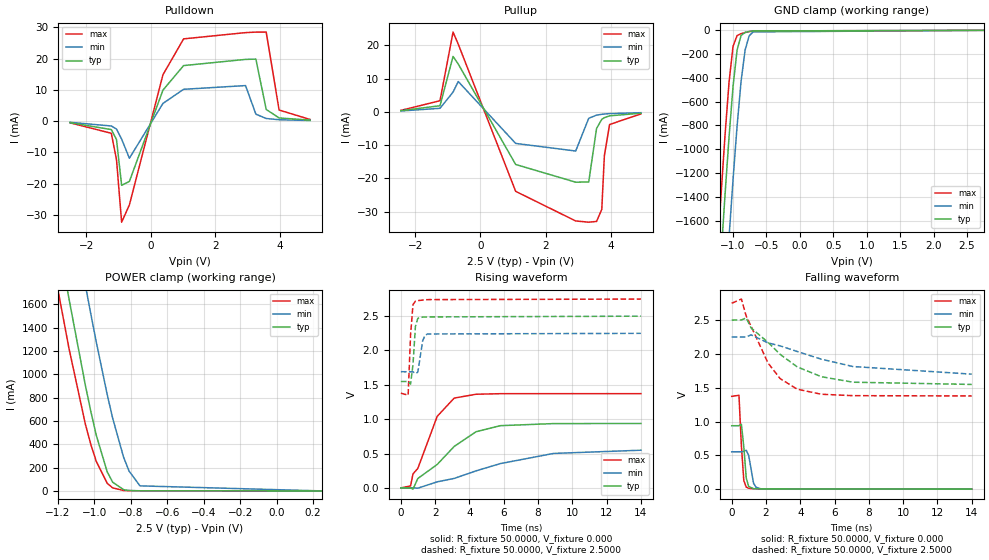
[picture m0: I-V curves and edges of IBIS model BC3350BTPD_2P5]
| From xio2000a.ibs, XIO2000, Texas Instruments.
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|   Model BC3350BTPD_2P5
[Model]   BC3350BTPD_2P5
Model_type   I/O
Polarity   Non-Inverting
Enable   Active-Low
Vinl =   0.7500V
Vinh =   1.7500V
Vmeas =   1.2500V
Cref =  15.0000pF
Rref = 100.0000M
Vref =  0.000V
C_comp   1.5797pF   1.6027pF   1.6241pF
[Model Spec]
|   typ   min   max
Vinh   1.750V   1.575V   1.925V
Vinl   0.750V   0.675V   0.825V
Vmeas   1.250V   1.125V   1.375V
[Temperature Range]   25.0000   0.1250k   -40.0000
[Voltage Range]   2.5000V   2.2500V   2.7500V
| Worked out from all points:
|   slope of the pulldown table from 0 to 0.375 V, typ, clamps not added: 38 ohm
|   slope of the pullup table from 0 to 0.375 V, typ, clamps not added: 54.3 ohm
|   GND clamp passes 1 mA (typ) near -0.59 V on its own axis
|   POWER clamp passes 1 mA (typ) near -0.75 V on its own axis
|   rising waveform, R_fixture 50.0000, V_fixture 0.000: 20-80 % time 2.32ns typ, 4.4ns min, 1.28ns max; typ from 0 V to 0.938 V
|   rising waveform, R_fixture 50.0000, V_fixture 2.5000: 20-80 % time 159ps typ, 199ps min, 172ps max; typ from 1.55 V to 2.5 V
|   falling waveform, R_fixture 50.0000, V_fixture 0.000: 20-80 % time 188ps typ, 231ps min, 187ps max; typ from 0.938 V to 0 V
|   falling waveform, R_fixture 50.0000, V_fixture 2.5000: 20-80 % time 2.84ns typ, 4.62ns min, 1.75ns max; typ from 2.5 V to 1.55 V
[Pulldown]
| voltage   I(typ)   I(min)   I(max)
-2.5V     -459uA     -348uA     -515uA
-1.22V    -2.677mA   -1.519mA   -3.847mA
-1.06V    -5.844mA   -2.506mA   -12.3mA
-900mV    -20.51mA   -5.737mA   -32.31mA
-660mV    -19.25mA   -11.84mA   -26.77mA
380mV     9.961mA    5.703mA    14.88mA
1.02V     17.81mA    10.22mA    26.36mA
2.94V     19.79mA    11.41mA    28.36mA
3.26V     19.88mA    2.268mA    28.52mA
3.58V     3.771mA    876.2uA    28.53mA
3.98V     1.046mA    481.3uA    3.587mA
4.94V     365uA      228uA      561uA
[Pullup]
| voltage   I(typ)   I(min)   I(max)
-2.44V    372uA      280uA      460uA
-1.24V    1.86mA     1.082mA    3.367mA
-840mV    16.68mA    5.954mA    24.02mA
-680mV    14.39mA    9.14mA     20.37mA
1.08V     -15.82mA   -9.485mA   -23.91mA
2.92V     -21.15mA   -11.77mA   -32.82mA
3.32V     -21.09mA   -1.924mA   -33.19mA
3.56V     -4.98mA    -966.7uA   -32.96mA
3.72V     -2.251mA   -717.3uA   -29.34mA
3.8V      -1.74mA    -634.4uA   -13.11mA
3.96V     -1.186mA   -514.3uA   -3.788mA
4.92V     -398uA     -238uA     -615uA
[GND_clamp]
| voltage   I(typ)   I(min)   I(max)
-2.5V     -14.57A    -15.39A    -14.11A
-1.24V    -2.434A    -3.317A    -1.918A
-1.18V    -1.899A    -2.778A    -1.385A
-1.12V    -1.382A    -2.25A     -881mA
-1.06V    -896.4mA   -1.74A     -435.4mA
-1V       -470.1mA   -1.253A    -133.5mA
-940mV    -166.1mA   -806.6mA   -44.23mA
-880mV    -43.23mA   -428.6mA   -27.9mA
-820mV    -17.49mA   -166.7mA   -18.56mA
-760mV    -9.789mA   -47.14mA   -10.93mA
-700mV    -5.179mA   -13.1mA    -5.218mA
2.75V     0A         0A         0A
[POWER_clamp]
| voltage   I(typ)   I(min)   I(max)
-2.49V    14.58A     15.42A     14.11A
-1.2V     2.177A     3.077A     1.722A
-1.14V    1.65A      2.542A     1.224A
-1.05V    907.7mA    1.767A     573.8mA
-1.02V    683.1mA    1.519A     399.5mA
-990mV    477.9mA    1.278A     253.5mA
-930mV    164mA      827.7mA    65.56mA
-900mV    74.97mA    624.5mA    26.15mA
-840mV    10.76mA    289.2mA    3.692mA
-810mV    4.115mA    170.7mA    1.895mA
-750mV    1.035mA    43.44mA    990.9uA
250mV     0A         0A         0A
[Ramp]
| variable   typ   min   max
dV/dt_r   0.5625/2.2941n   0.3290/4.4907n   0.8232/1.2718n
dV/dt_f   0.5705/2.8139n   0.3294/4.7136n   0.8221/1.7310n
R_load = 50.0000
[Rising Waveform]
R_fixture = 50.0000
V_fixture = 0.000
V_fixture_min = 0.000
V_fixture_max = 0.000
| time   V(typ)   V(min)   V(max)
0s        1.092nV    27.63nV    575.1pV
565.7ps   400.3uV    -183.7uV   29.17mV
707.1ps   -18.27mV   681.9uV    203.8mV
989.9ps   137mV      -3.827mV   284.1mV
2.121ns   341.5mV    88.39mV    1.042V
3.111ns   603.7mV    137.9mV    1.307V
4.384ns   817.6mV    248.1mV    1.363V
5.798ns   905.6mV    353.6mV    1.371V
8.909ns   936.1mV    501.8mV    1.372V
14ns      937.6mV    548.4mV    1.372V
[Rising Waveform]
R_fixture = 50.0000
V_fixture = 2.5000
V_fixture_min = 2.2500
V_fixture_max = 2.7500
| time   V(typ)   V(min)   V(max)
0s        1.548V     1.691V     1.378V
424.2ps   1.549V     1.69V      1.349V
565.7ps   1.511V     1.69V      2.225V
707.1ps   1.794V     1.69V      2.668V
848.5ps   2.349V     1.664V     2.717V
989.9ps   2.468V     1.685V     2.725V
1.273ns   2.486V     2.142V     2.733V
1.414ns   2.487V     2.221V     2.737V
1.556ns   2.488V     2.24V      2.74V
14ns      2.499V     2.249V     2.748V
[Falling Waveform]
R_fixture = 50.0000
V_fixture = 0.000
V_fixture_min = 0.000
V_fixture_max = 0.000
| time   V(typ)   V(min)   V(max)
0s        937.6mV    552.3mV    1.372V
424.2ps   938.1mV    553.3mV    1.388V
565.7ps   959.4mV    552.2mV    640.5mV
707.1ps   622.9mV    558.5mV    126.6mV
848.5ps   163.8mV    574.7mV    30.03mV
989.9ps   39.65mV    499.6mV    13.53mV
1.273ns   7.152mV    89.86mV    6.479mV
1.414ns   5.946mV    28.74mV    4.938mV
1.697ns   4.197mV    5.705mV    2.744mV
14ns      1.083uV    19.75uV    294nV
[Falling Waveform]
R_fixture = 50.0000
V_fixture = 2.5000
V_fixture_min = 2.2500
V_fixture_max = 2.7500
| time   V(typ)   V(min)   V(max)
0s        2.499V     2.249V     2.748V
565.7ps   2.501V     2.249V     2.81V
848.5ps   2.532V     2.249V     2.556V
1.131ns   2.382V     2.281V     2.409V
2.121ns   2.17V      2.162V     1.863V
2.828ns   1.992V     2.118V     1.634V
3.818ns   1.808V     2.035V     1.478V
5.232ns   1.662V     1.921V     1.403V
7.071ns   1.581V     1.813V     1.382V
14ns      1.548V     1.7V       1.378V
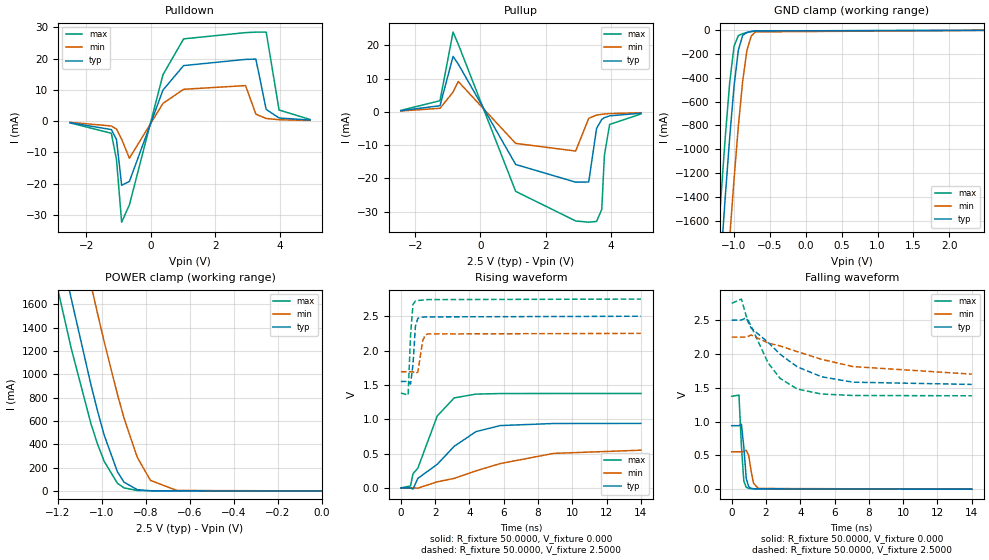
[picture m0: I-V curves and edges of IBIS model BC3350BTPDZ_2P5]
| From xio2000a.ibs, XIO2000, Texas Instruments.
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|   Model BC3350BTPDZ_2P5
[Model]   BC3350BTPDZ_2P5
Model_type   I/O
Polarity   Non-Inverting
Enable   Active-Low
Vinl =   0.7500V
Vinh =   1.7500V
Vmeas =   1.2500V
Cref =  15.0000pF
Rref = 100.0000M
Vref =  0.000V
C_comp   1.5797pF   1.6027pF   1.6241pF
[Model Spec]
|   typ   min   max
Vinh   1.750V   1.575V   1.925V
Vinl   0.750V   0.675V   0.825V
Vmeas   1.250V   1.125V   1.375V
[Temperature Range]   25.0000   0.1250k   -40.0000
[Voltage Range]   2.5000V   2.2500V   2.7500V
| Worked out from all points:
|   slope of the pulldown table from 0 to 0.375 V, typ, clamps not added: 38 ohm
|   slope of the pullup table from 0 to 0.375 V, typ, clamps not added: 54.3 ohm
|   GND clamp passes 1 mA (typ) near -0.59 V on its own axis
|   POWER clamp passes 1 mA (typ) near -0.75 V on its own axis
|   rising waveform, R_fixture 50.0000, V_fixture 0.000: 20-80 % time 2.32ns typ, 4.39ns min, 1.28ns max; typ from 0 V to 0.939 V
|   rising waveform, R_fixture 50.0000, V_fixture 2.5000: 20-80 % time 159ps typ, 199ps min, 171ps max; typ from 1.55 V to 2.5 V
|   falling waveform, R_fixture 50.0000, V_fixture 0.000: 20-80 % time 186ps typ, 229ps min, 186ps max; typ from 0.939 V to 0 V
|   falling waveform, R_fixture 50.0000, V_fixture 2.5000: 20-80 % time 2.84ns typ, 4.62ns min, 1.75ns max; typ from 2.5 V to 1.55 V
[Pulldown]
| voltage   I(typ)   I(min)   I(max)
-2.5V     -459uA     -348uA     -515uA
-1.22V    -2.677mA   -1.519mA   -3.847mA
-1.06V    -5.844mA   -2.506mA   -12.3mA
-900mV    -20.5mA    -5.737mA   -32.31mA
-660mV    -19.25mA   -11.84mA   -26.77mA
380mV     9.961mA    5.703mA    14.88mA
1.02V     17.81mA    10.22mA    26.36mA
2.94V     19.79mA    11.41mA    28.36mA
3.26V     19.88mA    2.268mA    28.52mA
3.58V     3.771mA    876.2uA    28.53mA
3.98V     1.046mA    481.2uA    3.587mA
4.94V     365uA      228uA      561uA
[Pullup]
| voltage   I(typ)   I(min)   I(max)
-2.44V    372uA      280uA      461uA
-1.24V    1.86mA     1.082mA    3.367mA
-840mV    16.68mA    5.954mA    24.02mA
-680mV    14.39mA    9.14mA     20.37mA
1.08V     -15.82mA   -9.485mA   -23.91mA
2.92V     -21.15mA   -11.77mA   -32.82mA
3.32V     -21.09mA   -1.924mA   -33.19mA
3.56V     -4.98mA    -966.6uA   -32.96mA
3.72V     -2.251mA   -717.3uA   -29.34mA
3.8V      -1.74mA    -634.3uA   -13.11mA
3.96V     -1.186mA   -514.3uA   -3.788mA
4.92V     -398uA     -238uA     -614uA
[GND_clamp]
| voltage   I(typ)   I(min)   I(max)
-2.5V     -14.57A    -15.39A    -14.11A
-1.24V    -2.434A    -3.317A    -1.918A
-1.18V    -1.899A    -2.778A    -1.385A
-1.12V    -1.382A    -2.25A     -881mA
-1.06V    -896.4mA   -1.74A     -435.3mA
-1V       -470.1mA   -1.253A    -133.5mA
-940mV    -166.1mA   -806.6mA   -44.14mA
-880mV    -43.19mA   -428.6mA   -27.79mA
-820mV    -17.44mA   -166.7mA   -18.46mA
-760mV    -9.734mA   -47.13mA   -10.84mA
-700mV    -5.127mA   -13.09mA   -5.132mA
2.48V     111.8pA    195nA      93.15pA
[POWER_clamp]
| voltage   I(typ)   I(min)   I(max)
-2.49V    14.58A     15.42A     14.11A
-1.2V     2.177A     3.077A     1.722A
-1.14V    1.65A      2.542A     1.223A
-1.05V    907.7mA    1.767A     573.8mA
-1.02V    683mA      1.519A     399.4mA
-990mV    477.9mA    1.278A     253.4mA
-930mV    163.9mA    827.7mA    65.48mA
-900mV    74.93mA    624.5mA    26.06mA
-840mV    10.71mA    289.2mA    3.596mA
-780mV    1.796mA    90.25mA    1.191mA
-660mV    334uA      3.822mA    368.9uA
0V        114.6pA    2.17nA     109.7pA
[Ramp]
| variable   typ   min   max
dV/dt_r   0.5636/2.2927n   0.3295/4.4889n   0.8251/1.2722n
dV/dt_f   0.5698/2.8110n   0.3291/4.7098n   0.8206/1.7291n
R_load = 50.0000
[Rising Waveform]
R_fixture = 50.0000
V_fixture = 0.000
V_fixture_min = 0.000
V_fixture_max = 0.000
| time   V(typ)   V(min)   V(max)
0s        1.093nV    27.66nV    576pV
565.7ps   408.4uV    -184.6uV   29.2mV
707.1ps   -18.38mV   683.7uV    206.9mV
989.9ps   138.7mV    -3.842mV   286.4mV
2.121ns   343.3mV    88.64mV    1.047V
3.111ns   606mV      138.4mV    1.311V
4.384ns   819.8mV    248.7mV    1.366V
5.798ns   907.6mV    354.4mV    1.374V
8.909ns   937.9mV    502.6mV    1.375V
14ns      939.4mV    549.1mV    1.375V
[Rising Waveform]
R_fixture = 50.0000
V_fixture = 2.5000
V_fixture_min = 2.2500
V_fixture_max = 2.7500
| time   V(typ)   V(min)   V(max)
0s        1.55V      1.692V     1.382V
424.2ps   1.551V     1.691V     1.353V
565.7ps   1.514V     1.692V     2.231V
707.1ps   1.797V     1.692V     2.672V
848.5ps   2.351V     1.666V     2.721V
989.9ps   2.47V      1.687V     2.728V
1.273ns   2.488V     2.143V     2.736V
1.414ns   2.489V     2.222V     2.74V
1.556ns   2.49V      2.242V     2.742V
14ns      2.5V       2.25V      2.75V
[Falling Waveform]
R_fixture = 50.0000
V_fixture = 0.000
V_fixture_min = 0.000
V_fixture_max = 0.000
| time   V(typ)   V(min)   V(max)
0s        939.4mV    553.1mV    1.375V
424.2ps   939.9mV    554mV      1.391V
565.7ps   961.4mV    552.9mV    638.3mV
707.1ps   622.8mV    559.3mV    120mV
848.5ps   158.8mV    575.6mV    26.76mV
989.9ps   35.93mV    500.1mV    12.03mV
1.131ns   10.8mV     270.6mV    7.945mV
1.273ns   6.201mV    87.45mV    5.873mV
1.556ns   4.498mV    10.04mV    3.41mV
14ns      1.082uV    19.67uV    292.4nV
[Falling Waveform]
R_fixture = 50.0000
V_fixture = 2.5000
V_fixture_min = 2.2500
V_fixture_max = 2.7500
| time   V(typ)   V(min)   V(max)
0s        2.5V       2.25V      2.75V
565.7ps   2.503V     2.25V      2.813V
848.5ps   2.535V     2.25V      2.56V
1.131ns   2.384V     2.281V     2.413V
2.121ns   2.173V     2.163V     1.868V
2.828ns   1.995V     2.119V     1.638V
3.818ns   1.811V     2.036V     1.482V
5.232ns   1.664V     1.922V     1.408V
7.071ns   1.583V     1.814V     1.386V
14ns      1.55V      1.702V     1.382V
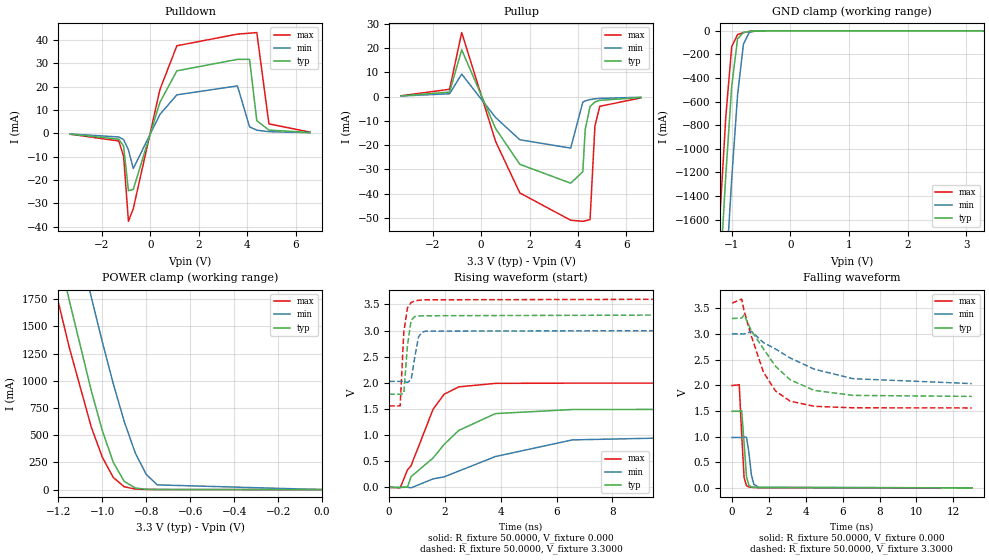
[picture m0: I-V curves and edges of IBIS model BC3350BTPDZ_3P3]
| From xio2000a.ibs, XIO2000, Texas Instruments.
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|   Model BC3350BTPDZ_3P3
[Model]   BC3350BTPDZ_3P3
Model_type   I/O
Polarity   Non-Inverting
Enable   Active-Low
Vinl =   0.9900V
Vinh =   2.3100V
Vmeas =   1.6500V
Cref =  15.0000pF
Rref = 100.0000M
Vref =  0.000V
C_comp   1.9708pF   2.0638pF   1.9731pF
[Model Spec]
|   typ   min   max
Vinh   2.31V   2.10V   2.52V
Vinl   0.99V   0.90V   1.08V
Vmeas   1.65V   1.50V   1.80V
[Temperature Range]   25.0000   0.1250k   -40.0000
[Voltage Range]   3.3000V   3.0000V   3.6000V
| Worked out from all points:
|   slope of the pulldown table from 0 to 0.495 V, typ, clamps not added: 31.4 ohm
|   slope of the pullup table from 0 to 0.495 V, typ, clamps not added: 44.5 ohm
|   GND clamp passes 1 mA (typ) near -0.59 V on its own axis
|   POWER clamp passes 1 mA (typ) near -0.75 V on its own axis
|   rising waveform, R_fixture 50.0000, V_fixture 0.000: 20-80 % time 1.63ns typ, 3.18ns min, 928ps max; typ from 0 V to 1.49 V
|   rising waveform, R_fixture 50.0000, V_fixture 3.3000: 20-80 % time 167ps typ, 189ps min, 156ps max; typ from 1.78 V to 3.3 V
|   falling waveform, R_fixture 50.0000, V_fixture 0.000: 20-80 % time 181ps typ, 217ps min, 176ps max; typ from 1.49 V to 0 V
|   falling waveform, R_fixture 50.0000, V_fixture 3.3000: 20-80 % time 2.06ns typ, 3.39ns min, 1.33ns max; typ from 3.3 V to 1.78 V
[Pulldown]
| voltage   I(typ)   I(min)   I(max)
-3.3V     -363uA     -289uA     -392uA
-1.3V     -2.499mA   -1.558mA   -3.272mA
-1.1V     -5.495mA   -2.673mA   -9.753mA
-900mV    -24.57mA   -7.086mA   -37.63mA
-700mV    -23.98mA   -15.08mA   -32.22mA
400mV     13.29mA    8.099mA    18.71mA
1.1V      26.74mA    16.46mA    37.45mA
3.6V      31.62mA    20.28mA    42.43mA
4.1V      31.65mA    2.775mA    42.82mA
4.4V      5.418mA    1.337mA    43.09mA
4.9V      1.364mA    700.9uA    4.045mA
6.6V      367uA      263uA      482uA
[Pullup]
| voltage   I(typ)   I(min)   I(max)
-3.3V     276uA      222uA      319uA
-1.3V     1.831mA    1.157mA    3.006mA
-800mV    19.29mA    9.256mA    26.38mA
600mV     -13.2mA    -8.655mA   -18.5mA
1.6V      -27.94mA   -17.82mA   -39.75mA
3.7V      -35.73mA   -21.26mA   -51mA
4.2V      -31.01mA   -2.304mA   -51.44mA
4.3V      -13.58mA   -1.804mA   -51.23mA
4.5V      -4.094mA   -1.249mA   -50.72mA
4.7V      -2.272mA   -950.1uA   -12.21mA
4.9V      -1.556mA   -765.1uA   -4.03mA
6.6V      -413uA     -285uA     -545uA
[GND_clamp]
| voltage   I(typ)   I(min)   I(max)
-3.3V     -22.46A    -23.25A    -22.02A
-1.3V     -2.981A    -3.864A    -2.466A
-1.2V     -2.075A    -2.956A    -1.561A
-1.1V     -1.216A    -2.078A    -723.3mA
-1V       -470.1mA   -1.253A    -133.5mA
-900mV    -66.71mA   -544.3mA   -31.64mA
-800mV    -14.21mA   -112.3mA   -15.74mA
-700mV    -5.127mA   -13.09mA   -5.132mA
-600mV    -1.059mA   -2.3mA     -715.9uA
-400mV    -6.019uA   -45.28uA   -1.112uA
3.3V      155.2pA    1.105uA    124.9pA
[POWER_clamp]
| voltage   I(typ)   I(min)   I(max)
-3.3V     22.56A     23.38A     22.11A
-1.25V    2.627A     3.53A      2.158A
-1.2V     2.177A     3.077A     1.722A
-1.15V    1.736A     2.631A     1.304A
-1.05V    907.7mA    1.767A     573.8mA
-1V       543.6mA    1.358A     298.7mA
-950mV    250.4mA    972.4mA    111.1mA
-900mV    74.93mA    624.5mA    26.06mA
-850mV    15.02mA    336.8mA    4.862mA
-800mV    3.029mA    139.7mA    1.53mA
-750mV    983.5uA    43.42mA    893.5uA
0V        155.2pA    2.74nA     144.1pA
[Ramp]
| variable   typ   min   max
dV/dt_r   0.8954/1.6133n   0.5882/3.1510n   1.1967/0.9192n
dV/dt_f   0.9109/2.0429n   0.5806/3.3595n   1.2256/1.3213n
R_load = 50.0000
[Rising Waveform]
R_fixture = 50.0000
V_fixture = 0.000
V_fixture_min = 0.000
V_fixture_max = 0.000
| time   V(typ)   V(min)   V(max)
0s        1.535nV    33.99nV    724.7pV
393.9ps   892.9uV    -12.59uV   -9.215mV
656.6ps   6.864mV    1.945mV    333.6mV
787.9ps   205.4mV    -8.264mV   417.5mV
1.576ns   562.5mV    162.9mV    1.495V
1.97ns    820.4mV    200.7mV    1.781V
2.495ns   1.089V     311.8mV    1.922V
3.808ns   1.411V     589.5mV    1.989V
6.566ns   1.489V     908mV      1.994V
13ns      1.492V     980.3mV    1.994V
[Rising Waveform]
R_fixture = 50.0000
V_fixture = 3.3000
V_fixture_min = 3.0000
V_fixture_max = 3.6000
| time   V(typ)   V(min)   V(max)
0s        1.782V     2.028V     1.557V
393.9ps   1.782V     2.027V     1.558V
525.3ps   1.796V     2.029V     2.971V
656.6ps   2.718V     2.006V     3.434V
787.9ps   3.195V     2.059V     3.535V
919.2ps   3.267V     2.492V     3.567V
1.051ns   3.277V     2.877V     3.578V
1.182ns   3.28V      2.969V     3.583V
1.313ns   3.282V     2.988V     3.587V
13ns      3.3V       3V         3.6V
[Falling Waveform]
R_fixture = 50.0000
V_fixture = 0.000
V_fixture_min = 0.000
V_fixture_max = 0.000
| time   V(typ)   V(min)   V(max)
0s        1.492V     981.6mV    1.994V
393.9ps   1.493V     982.5mV    2.009V
525.3ps   1.504V     981.5mV    1.04V
656.6ps   872.4mV    993.1mV    201.7mV
787.9ps   215mV      984.3mV    42.64mV
919.2ps   48.51mV    684.9mV    15.65mV
1.051ns   16.52mV    255.2mV    10.73mV
1.182ns   10.39mV    70.59mV    7.904mV
1.444ns   6.791mV    9.904mV    4.275mV
13ns      677.3nV    10.11uV    291.6nV
[Falling Waveform]
R_fixture = 50.0000
V_fixture = 3.3000
V_fixture_min = 3.0000
V_fixture_max = 3.6000
| time   V(typ)   V(min)   V(max)
0s        3.3V       3V         3.6V
525.3ps   3.31V      3V         3.678V
656.6ps   3.369V     2.997V     3.449V
1.051ns   3.063V     3.05V      2.956V
1.707ns   2.71V      2.831V     2.253V
2.364ns   2.368V     2.707V     1.886V
3.152ns   2.107V     2.531V     1.69V
4.465ns   1.899V     2.312V     1.589V
6.566ns   1.802V     2.127V     1.56V
13ns      1.782V     2.032V     1.557V
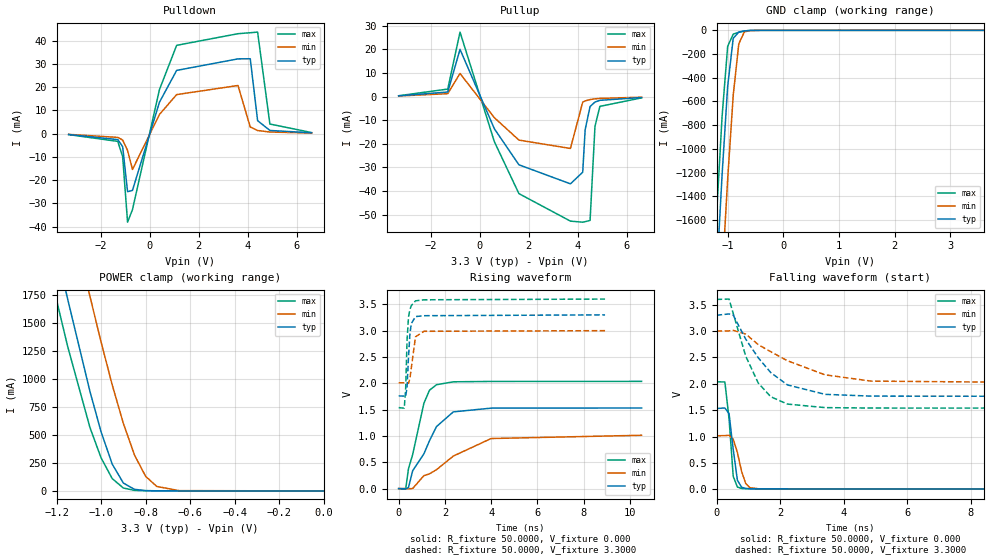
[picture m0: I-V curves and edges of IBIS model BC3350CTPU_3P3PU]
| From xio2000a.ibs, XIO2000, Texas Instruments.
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|   Model BC3350CTPU_3P3PU
[Model]   BC3350CTPU_3P3PU
Model_type   I/O
Polarity   Non-Inverting
Enable   Active-Low
Vinl =   0.9900V
Vinh =   2.3100V
Vmeas =   1.6500V
Cref =  15.0000pF
Rref = 100.0000M
Vref =  0.000V
C_comp   1.9215pF   2.0161pF   1.9194pF
[Temperature Range]   25.0000   0.1250k   -40.0000
[Voltage Range]   3.3000V   3.0000V   3.6000V
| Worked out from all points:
|   slope of the pulldown table from 0 to 0.495 V, typ, clamps not added: 30.8 ohm
|   slope of the pullup table from 0 to 0.495 V, typ, clamps not added: 43 ohm
|   GND clamp passes 1 mA (typ) near -0.58 V on its own axis
|   POWER clamp passes 1 mA (typ) near -0.74 V on its own axis
|   rising waveform, R_fixture 50.0000, V_fixture 0.000: 20-80 % time 1.13ns typ, 2.16ns min, 657ps max; typ from 0.002 V to 1.53 V
|   rising waveform, R_fixture 50.0000, V_fixture 3.3000: 20-80 % time 125ps typ, 163ps min, 108ps max; typ from 1.76 V to 3.3 V
|   falling waveform, R_fixture 50.0000, V_fixture 0.000: 20-80 % time 192ps typ, 268ps min, 166ps max; typ from 1.53 V to 0.002 V
|   falling waveform, R_fixture 50.0000, V_fixture 3.3000: 20-80 % time 1.21ns typ, 2.01ns min, 802ps max; typ from 3.3 V to 1.76 V
[Pulldown]
| voltage   I(typ)   I(min)   I(max)
-3.3V     -368uA     -295uA     -396uA
-1.3V     -2.536mA   -1.588mA   -3.308mA
-1.1V     -5.574mA   -2.722mA   -9.853mA
-900mV    -24.94mA   -7.21mA    -38.07mA
-700mV    -24.39mA   -15.39mA   -32.64mA
400mV     13.55mA    8.28mA     19mA
1.1V      27.23mA    16.82mA    38.01mA
3.6V      32.19mA    20.74mA    43.02mA
4.1V      32.24mA    2.869mA    43.43mA
4.4V      5.593mA    1.375mA    43.71mA
4.9V      1.396mA    719.1uA    4.161mA
6.6V      374uA      270uA      490uA
[Pullup]
| voltage   I(typ)   I(min)   I(max)
-3.3V     287uA      231uA      331uA
-1.3V     1.913mA    1.209mA    3.156mA
-800mV    19.97mA    9.765mA    27.29mA
600mV     -13.66mA   -8.958mA   -19.14mA
1.6V      -28.91mA   -18.45mA   -41.12mA
3.7V      -36.98mA   -22mA      -52.77mA
4.2V      -32.06mA   -2.382mA   -53.22mA
4.3V      -14.02mA   -1.866mA   -53mA
4.5V      -4.234mA   -1.292mA   -52.47mA
4.7V      -2.35mA    -983uA     -12.63mA
4.9V      -1.61mA    -791.8uA   -4.169mA
6.6V      -427uA     -295uA     -564uA
[GND_clamp]
| voltage   I(typ)   I(min)   I(max)
-3.3V     -22.46A    -23.25A    -22.02A
-1.3V     -2.984A    -3.868A    -2.468A
-1.2V     -2.078A    -2.96A     -1.563A
-1.1V     -1.218A    -2.081A    -725.3mA
-1V       -472.1mA   -1.256A    -134.6mA
-900mV    -67.44mA   -546.8mA   -32.21mA
-800mV    -14.49mA   -113.3mA   -16.11mA
-700mV    -5.296mA   -13.28mA   -5.367mA
-600mV    -1.174mA   -2.386mA   -889.7uA
-400mV    -107.2uA   -106uA     -164.8uA
3.6V      0A         0A         0A
[POWER_clamp]
| voltage   I(typ)   I(min)   I(max)
-3.3V     22.54A     23.35A     22.1A
-1.2V     2.157A     3.049A     1.709A
-1.15V    1.717A     2.603A     1.293A
-1.05V    891mA      1.742A     568.1mA
-1V       529.4mA    1.333A     296.2mA
-950mV    240.5mA    949.8mA    110.5mA
-900mV    70.83mA    604.8mA    26.11mA
-850mV    14.22mA    321.8mA    5.008mA
-800mV    2.986mA    131.1mA    1.668mA
-750mV    1.048mA    40.21mA    1.014mA
-650mV    361.8uA    2.754mA    415.4uA
0V        145pA      2.769nA    132.7pA
[Ramp]
| variable   typ   min   max
dV/dt_r   0.9181/1.1046n   0.6075/2.1596n   1.2207/0.6398n
dV/dt_f   0.9236/1.1963n   0.5942/1.9892n   1.2365/0.7942n
R_load = 50.0000
[Rising Waveform]
R_fixture = 50.0000
V_fixture = 0.000
V_fixture_min = 0.000
V_fixture_max = 0.000
| time   V(typ)   V(min)   V(max)
0s        1.67mV     1.354mV    2.118mV
303ps     -2.132mV   2.789mV    -9.431mV
424.2ps   21.33mV    -2.054mV   379.1mV
606.1ps   341.8mV    2.808mV    649.1mV
1.091ns   660.8mV    247.5mV    1.621V
1.333ns   910.6mV    281.5mV    1.869V
1.636ns   1.179V     360.4mV    1.974V
2.364ns   1.458V     619.1mV    2.029V
4ns       1.529V     952.1mV    2.036V
10.51ns   1.532V     1.014V     2.037V
[Rising Waveform]
R_fixture = 50.0000
V_fixture = 3.3000
V_fixture_min = 3.0000
V_fixture_max = 3.6000
| time   V(typ)   V(min)   V(max)
0s        1.761V     2.01V      1.539V
242.4ps   1.757V     2.011V     1.528V
303ps     1.748V     2.008V     1.903V
363.6ps   1.937V     1.995V     2.824V
424.2ps   2.489V     2.001V     3.256V
484.8ps   2.933V     2.084V     3.401V
545.5ps   3.135V     2.288V     3.474V
727.3ps   3.267V     2.883V     3.566V
1.091ns   3.284V     2.988V     3.586V
8.929ns   3.3V       3V         3.6V
[Falling Waveform]
R_fixture = 50.0000
V_fixture = 0.000
V_fixture_min = 0.000
V_fixture_max = 0.000
| time   V(typ)   V(min)   V(max)
0s        1.532V     1.014V     2.037V
262.6ps   1.541V     1.017V     2.035V
393.9ps   1.435V     1.023V     1.339V
525.3ps   753.3mV    946.7mV    244.8mV
656.6ps   170.8mV    697.9mV    41.65mV
787.9ps   37.54mV    339.3mV    14.43mV
919.2ps   15.12mV    107mV      10.58mV
1.051ns   10.2mV     29.18mV    8.496mV
1.313ns   7.196mV    8.953mV    5.843mV
13ns      1.671mV    1.355mV    2.118mV
[Falling Waveform]
R_fixture = 50.0000
V_fixture = 3.3000
V_fixture_min = 3.0000
V_fixture_max = 3.6000
| time   V(typ)   V(min)   V(max)
0s        3.3V       3V         3.6V
393.9ps   3.325V     3.003V     3.607V
525.3ps   3.303V     3.013V     3.333V
919.2ps   2.846V     2.943V     2.523V
1.313ns   2.493V     2.743V     2.014V
1.707ns   2.212V     2.608V     1.754V
2.232ns   1.978V     2.437V     1.615V
3.414ns   1.8V       2.17V      1.548V
4.859ns   1.766V     2.051V     1.54V
13ns      1.761V     2.01V      1.539V
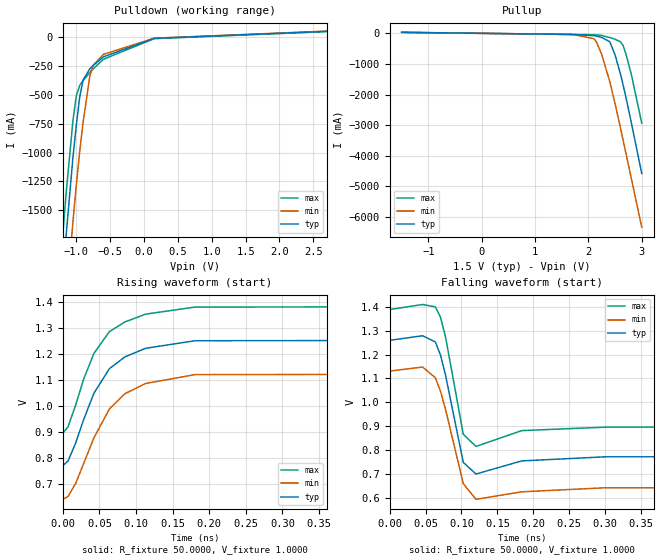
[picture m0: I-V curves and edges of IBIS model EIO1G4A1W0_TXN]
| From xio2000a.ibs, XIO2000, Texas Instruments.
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|   Model EIO1G4A1W0_TXN
[Model]   EIO1G4A1W0_TXN
Model_type   Output
Polarity   Inverting
Vmeas =   1.0000V
Cref =   5.0000pF
Rref =  50.0000
Vref =   1.0000V
C_comp   1.6030pF   1.6370pF   1.5940pF
[Temperature Range]   25.0000   0.1250k   -40.0000
[Voltage Range]   1.5000V   1.3500V   1.6500V
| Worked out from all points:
|   slope of the pulldown table from 0 to 0.225 V, typ, clamps not added: 10 ohm
|   slope of the pullup table from 0 to 0.225 V, typ, clamps not added: 46 ohm
|   rising waveform, R_fixture 50.0000, V_fixture 1.0000: 20-80 % time 51.5ps typ, 55.3ps min, 49.4ps max; typ from 0.771 V to 1.26 V
|   falling waveform, R_fixture 50.0000, V_fixture 1.0000: 20-80 % time 20.7ps typ, 23.5ps min, 18.6ps max; typ from 1.26 V to 0.771 V
[Pulldown]
| voltage   I(typ)   I(min)   I(max)
-1.5V     -4.594A    -5.121A    -4.265A
-1.2V     -2.088A    -2.699A    -1.715A
-1.15V    -1.711A    -2.315A    -1.349A
-1.05V    -1.044A    -1.599A    -725.2mA
-1V       -764.5mA   -1.279A    -509.2mA
-950mV    -519.8mA   -991.5mA   -420.4mA
-900mV    -374.6mA   -737.8mA   -377.8mA
-800mV    -276.3mA   -337.6mA   -309.1mA
-750mV    -247.3mA   -245.7mA   -276.8mA
-600mV    -173.7mA   -152.2mA   -194.5mA
150mV     -13.82mA   -12.24mA   -16.25mA
3V        53.89mA    56.06mA    51.37mA
[Pullup]
| voltage   I(typ)   I(min)   I(max)
-1.5V     32.86mA    32.06mA    33.4mA
1.7V      -36.49mA   -36.27mA   -37.34mA
2.1V      -73.38mA   -171.4mA   -47.12mA
2.15V     -90.76mA   -274.2mA   -50.59mA
2.25V     -134.3mA   -692.4mA   -69.55mA
2.4V      -273mA     -1.573A    -136.4mA
2.5V      -704.7mA   -2.297A    -194.4mA
2.6V      -1.321A    -3.082A    -274.5mA
2.65V     -1.68A     -3.486A    -397mA
2.7V      -2.064A    -3.891A    -652.6mA
2.8V      -2.879A    -4.703A    -1.302A
3V        -4.58A     -6.332A    -2.931A
[Ramp]
| variable   typ   min   max
dV/dt_r   0.5584/44.3883p   0.5611/45.7199p   0.5597/43.7523p
dV/dt_f   0.5574/44.3490p   0.5591/45.0689p   0.5594/43.5451p
R_load = 50.0000
[Rising Waveform]
R_fixture = 50.0000
V_fixture = 1.0000
V_fixture_min = 0.9000
V_fixture_max = 1.1000
| time   V(typ)   V(min)   V(max)
0s        770.8mV    641.7mV    895.5mV
7.071ps   788.1mV    652.4mV    919.2mV
17.68ps   858.4mV    703.3mV    1.004V
28.28ps   945.7mV    777.7mV    1.101V
42.42ps   1.048V     877.1mV    1.201V
63.64ps   1.143V     988.3mV    1.285V
84.85ps   1.188V     1.047V     1.322V
113.1ps   1.221V     1.086V     1.352V
180.3ps   1.25V      1.12V      1.379V
3.03ns    1.26V      1.131V     1.389V
[Falling Waveform]
R_fixture = 50.0000
V_fixture = 1.0000
V_fixture_min = 0.9000
V_fixture_max = 1.1000
| time   V(typ)   V(min)   V(max)
0s        1.26V      1.131V     1.389V
45.96ps   1.279V     1.148V     1.41V
63.64ps   1.253V     1.103V     1.4V
70.71ps   1.199V     1.047V     1.357V
77.78ps   1.114V     970.5mV    1.274V
102.5ps   748.3mV    659.3mV    866.3mV
120.2ps   699.7mV    593.7mV    815.3mV
183.8ps   754.7mV    625.2mV    881.7mV
300.5ps   771.9mV    642.2mV    896.1mV
16.36ns   770.7mV    641.6mV    895.4mV
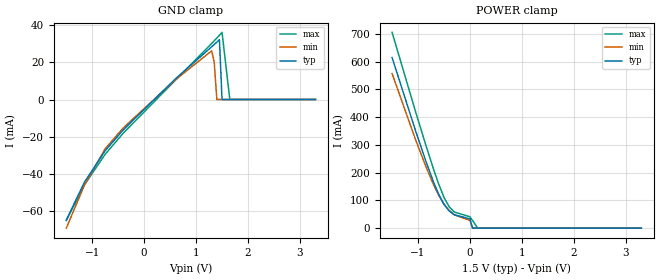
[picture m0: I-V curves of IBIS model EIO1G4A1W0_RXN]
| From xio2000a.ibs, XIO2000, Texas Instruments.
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|   Model EIO1G4A1W0_RXN
[Model]   EIO1G4A1W0_RXN
Model_type   Input
Polarity   Inverting
Vinl =  -0.6000V
Vinh =   0.6000V
C_comp   1.6030pF   1.6370pF   1.5940pF
[Model Spec]
|   typ   min   max
Vinh   0.5V   0.175V   0.6V
Vinl   -0.5V   -0.175V   -0.6V
[Temperature Range]   25.0000   0.1250k   -40.0000
[Voltage Range]   1.5000V   1.3500V   1.6500V
[GND_clamp]
| voltage   I(typ)   I(min)   I(max)
-1.5V     -64.97mA   -69.31mA   -65.2mA
-1.15V    -44.52mA   -46.11mA   -45.96mA
-750mV    -27.56mA   -26.49mA   -29.48mA
-400mV    -16.25mA   -15.22mA   -18.06mA
600mV     11.08mA    10.55mA    10.36mA
1.3V      28.4mA     26.23mA    30.18mA
1.35V     29.62mA    20mA       31.65mA
1.4V      30.89mA    0A         33.14mA
1.45V     32.23mA    0A         34.64mA
1.5V      0A         0A         36.17mA
1.65V     0A         0A         0A
3.3V      0A         0A         0A
[POWER_clamp]
| voltage   I(typ)   I(min)   I(max)
-1.5V     614.8mA    557.3mA    705.7mA
-1.05V    352.1mA    319.7mA    421.1mA
-850mV    241.7mA    222.3mA    299mA
-700mV    165.3mA    156mA      211.5mA
-600mV    120.8mA    117.7mA    157.4mA
-500mV    85.49mA    86.52mA    110.5mA
-400mV    61.9mA     63.55mA    76.75mA
-300mV    47.91mA    47.78mA    57.85mA
0V        33.62mA    27.69mA    41.02mA
50mV      0A         0A         27.35mA
150mV     0A         0A         0A
3.3V      0A         0A         0A
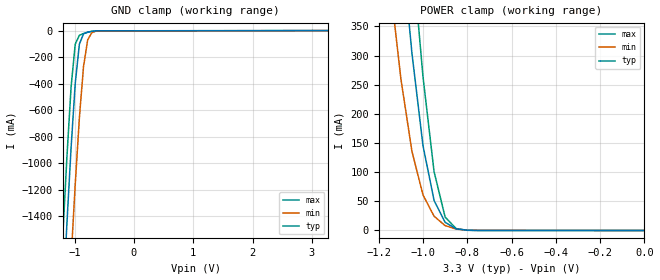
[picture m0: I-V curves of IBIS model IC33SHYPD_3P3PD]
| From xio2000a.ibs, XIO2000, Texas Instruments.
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|   Model IC33SHYPD_3P3PD
[Model]   IC33SHYPD_3P3PD
Model_type   Input
Polarity   Non-Inverting
Vinl =   0.9900V
Vinh =   2.3100V
C_comp   2.0800pF   2.0800pF   2.0800pF
[Model Spec]
|   typ   min   max
Vinh   2.31V   2.10V   2.52V
Vinl   0.99V   0.90V   1.08V
[Temperature Range]   25.0000   0.1250k   -40.0000
[Voltage Range]   3.3000V   3.0000V   3.6000V
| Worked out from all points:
|   GND clamp passes 1 mA (typ) near -0.59 V on its own axis
|   POWER clamp passes 1 mA (typ) near -0.81 V on its own axis
| (Vdd votage range)   1.50V   1.35V   1.65V
| (Process strength)   nominal   weak   strong
[GND_clamp]
| voltage   I(typ)   I(min)   I(max)
-3.3V     -22.44A    -23.23A    -22.01A
-1.2V     -2.062A    -2.938A    -1.55A
-1.13V    -1.453A    -2.319A    -952.1mA
-1.06V    -884.3mA   -1.722A    -427mA
-990mV    -399.1mA   -1.159A    -102.3mA
-920mV    -102mA     -657.3mA   -35.66mA
-850mV    -24.66mA   -270.7mA   -22.38mA
-780mV    -11.46mA   -70.03mA   -12.94mA
-710mV    -5.644mA   -15.31mA   -5.841mA
-640mV    -2.142mA   -4.307mA   -1.755mA
3.28V     193.2pA    3.222nA    168.3pA
[POWER_clamp]
| voltage   I(typ)   I(min)   I(max)
-3.3V     12.64A     11.74A     13.39A
-1.15V    732.8mA    427.8mA    979.7mA
-1.1V     506.2mA    260.6mA    722.8mA
-1.05V    304.3mA    136mA      480.1mA
-1V       145.5mA    61.04mA    263.8mA
-950mV    51.56mA    24.44mA    101mA
-900mV    14.01mA    8.383mA    22.94mA
-850mV    2.793mA    2.36mA     3.142mA
-800mV    442.5uA    587.5uA    300.2uA
-750mV    66.2uA     140.7uA    26.86uA
0V        195.4pA    2.747nA    187.9pA
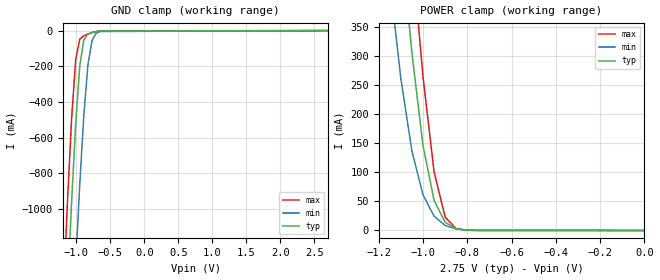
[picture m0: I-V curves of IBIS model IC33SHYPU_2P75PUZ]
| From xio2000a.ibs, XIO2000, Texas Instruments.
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|   Model IC33SHYPU_2P75PUZ
[Model]   IC33SHYPU_2P75PUZ
Model_type   Input
Polarity   Non-Inverting
Vinl =   0.8200V
Vinh =   1.9300V
C_comp   1.6800pF   1.6800pF   1.6800pF
[Temperature Range]   25.0000   0.1250k   -40.0000
[Voltage Range]   2.7500V   2.5000V   3.0000V
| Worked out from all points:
|   GND clamp passes 1 mA (typ) near -0.60 V on its own axis
|   POWER clamp passes 1 mA (typ) near -0.81 V on its own axis
[GND_clamp]
| voltage   I(typ)   I(min)   I(max)
-2.75V    -17.02A    -17.82A    -16.57A
-1.19V    -1.973A    -2.848A    -1.462A
-1.13V    -1.453A    -2.319A    -952mA
-1.07V    -961.9mA   -1.806A    -494.2mA
-1.01V    -524.4mA   -1.315A    -162.9mA
-950mV    -197.8mA   -862.4mA   -48.41mA
-890mV    -51.2mA    -472.9mA   -28.94mA
-830mV    -18.95mA   -192.8mA   -19.47mA
-770mV    -10.44mA   -56.11mA   -11.77mA
-710mV    -5.643mA   -15.28mA   -5.841mA
-650mV    -2.514mA   -5.077mA   -2.147mA
2.71V     148pA      3.084nA    129.4pA
[POWER_clamp]
| voltage   I(typ)   I(min)   I(max)
-2.75V    9.52A      8.73A      10.17A
-1.15V    732.9mA    428mA      979.8mA
-1.1V     506.3mA    260.8mA    722.9mA
-1.05V    304.4mA    136.2mA    480.2mA
-1V       145.7mA    61.22mA    263.9mA
-950mV    51.67mA    24.6mA     101mA
-900mV    14.1mA     8.529mA    22.97mA
-850mV    2.852mA    2.482mA    3.15mA
-800mV    471.9uA    685.4uA    302.8uA
-750mV    76.24uA    214.6uA    28.26uA
0V        151.6pA    2.342nA    146.6pA
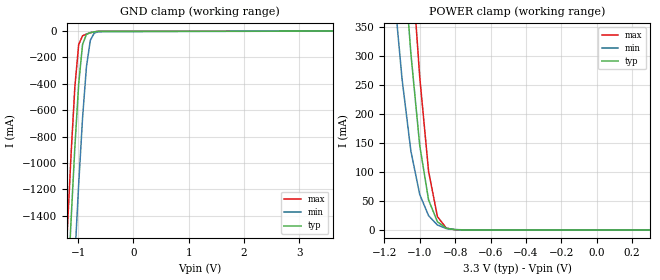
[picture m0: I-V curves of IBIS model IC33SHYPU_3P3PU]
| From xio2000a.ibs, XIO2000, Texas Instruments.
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|   Model IC33SHYPU_3P3PU
[Model]   IC33SHYPU_3P3PU
Model_type   Input
Polarity   Non-Inverting
Vinl =   0.9900V
Vinh =   2.3100V
C_comp   2.0800pF   2.0800pF   2.0800pF
[Temperature Range]   25.0000   0.1250k   -40.0000
[Voltage Range]   3.3000V   3.0000V   3.6000V
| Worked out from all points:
|   GND clamp passes 1 mA (typ) near -0.59 V on its own axis
|   POWER clamp passes 1 mA (typ) near -0.81 V on its own axis
[GND_clamp]
| voltage   I(typ)   I(min)   I(max)
-3.3V     -22.44A    -23.23A    -22.01A
-1.2V     -2.062A    -2.938A    -1.55A
-1.13V    -1.453A    -2.319A    -952.1mA
-1.06V    -884.3mA   -1.722A    -427mA
-990mV    -399.1mA   -1.159A    -102.3mA
-920mV    -102mA     -657.3mA   -35.8mA
-850mV    -24.73mA   -270.7mA   -22.54mA
-780mV    -11.56mA   -70.04mA   -13.1mA
-710mV    -5.743mA   -15.34mA   -6.004mA
-640mV    -2.243mA   -4.356mA   -1.919mA
3.6V      0A         17uA       0A
[POWER_clamp]
| voltage   I(typ)   I(min)   I(max)
-3.3V     12.64A     11.74A     13.39A
-1.15V    732.9mA    428mA      979.8mA
-1.1V     506.3mA    260.8mA    722.9mA
-1.05V    304.4mA    136.2mA    480.2mA
-1V       145.7mA    61.22mA    263.9mA
-950mV    51.68mA    24.61mA    101.1mA
-900mV    14.11mA    8.533mA    23.04mA
-850mV    2.879mA    2.487mA    3.244mA
-800mV    512.7uA    692.1uA    396.8uA
-750mV    128.4uA    223.3uA    117.1uA
300mV     0A         1nA        0A
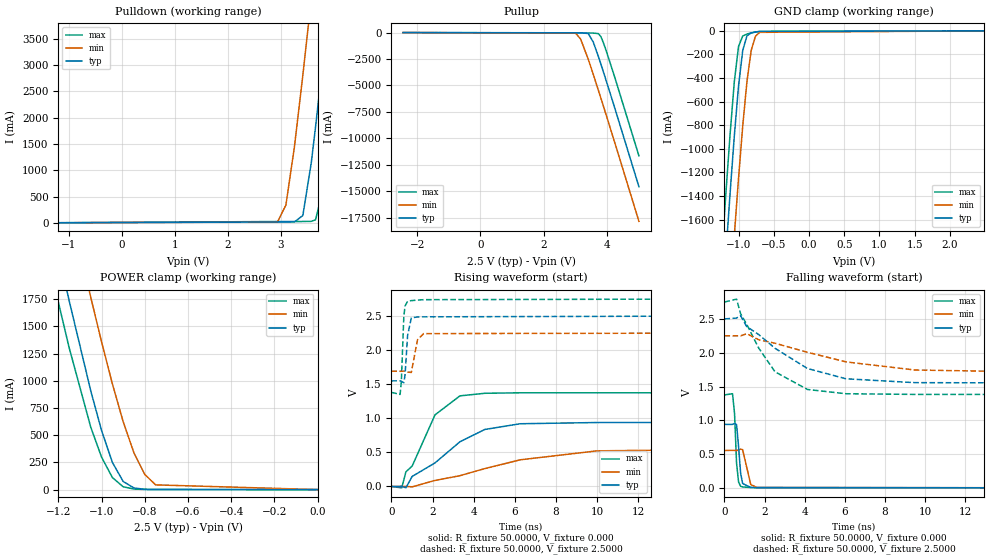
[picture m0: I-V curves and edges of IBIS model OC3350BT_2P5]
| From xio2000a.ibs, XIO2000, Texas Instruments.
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|************************ OC3350BT @ 2.5V************************
[Model]   OC3350BT_2P5
Model_type   3-state
Enable   Active-Low
Polarity   Non-Inverting
|Vinh =   1.75V
|Vinl =   0.75V
Vmeas = 1.25V
Cref = 15pF
Rref = 100e+06
Vref = 0V
|   typ   min   max
C_comp   1.579pF   1.602pF   1.574pF
|   typ   min   max
[Temperature Range]   25   125   -40
|   typ   min   max
[Voltage Range]   2.50V   2.25V   2.75V
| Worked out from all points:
|   slope of the pulldown table from 0 to 0.375 V, typ, clamps not added: 38 ohm
|   slope of the pullup table from 0 to 0.375 V, typ, clamps not added: 54.3 ohm
|   GND clamp passes 1 mA (typ) near -0.59 V on its own axis
|   POWER clamp passes 1 mA (typ) near -0.75 V on its own axis
|   rising waveform, R_fixture 50.0000, V_fixture 0.000: 20-80 % time 2.31ns typ, 4.48ns min, 1.28ns max; typ from 0 V to 0.939 V
|   rising waveform, R_fixture 50.0000, V_fixture 2.5000: 20-80 % time 135ps typ, 178ps min, 105ps max; typ from 1.55 V to 2.5 V
|   falling waveform, R_fixture 50.0000, V_fixture 0.000: 20-80 % time 164ps typ, 215ps min, 132ps max; typ from 0.939 V to 0 V
|   falling waveform, R_fixture 50.0000, V_fixture 2.5000: 20-80 % time 2.84ns typ, 4.8ns min, 1.74ns max; typ from 2.5 V to 1.55 V
[Pulldown]
| voltage   I(typ)   I(min)   I(max)
-2.5V     -459uA     -348uA     -514uA
2.94V     19.8mA     20.07mA    28.36mA
3.1V      20.01mA    342.7mA    28.44mA
3.26V     21.05mA    1.44A      28.55mA
3.42V     142.4mA    2.809A     29.01mA
3.58V     1.15A      4.266A     31.28mA
3.66V     1.826A     5.01A      61.56mA
3.82V     3.271A     6.52A      713.2mA
3.98V     4.772A     8.047A     1.985A
4.22V     7.068A     10.36A     4.189A
4.3V      7.841A     11.14A     4.948A
4.94V     14.09A     17.38A     11.16A
[Pullup]
| voltage   I(typ)   I(min)   I(max)
-2.44V    372uA      280uA      461uA
3V        -21.32mA   -48.48mA   -32.91mA
3.16V     -24.2mA    -610.7mA   -33.07mA
3.4V      -84.73mA   -2.514A    -35.27mA
3.56V     -901.3mA   -3.957A    -49.79mA
3.72V     -2.256A    -5.446A    -97.95mA
3.8V      -2.983A    -6.202A    -384.3mA
3.88V     -3.725A    -6.962A    -968.3mA
3.96V     -4.477A    -7.726A    -1.653A
4.2V      -6.769A    -10.04A    -3.875A
4.28V     -7.542A    -10.81A    -4.638A
5V        -14.57A    -17.84A    -11.65A
[GND_clamp]
| voltage   I(typ)   I(min)   I(max)
-2.5V     -14.57A    -15.39A    -14.11A
-1.24V    -2.434A    -3.317A    -1.918A
-1.18V    -1.899A    -2.778A    -1.385A
-1.12V    -1.382A    -2.25A     -880.9mA
-1.06V    -896.3mA   -1.739A    -435.1mA
-1V       -469.9mA   -1.253A    -133mA
-940mV    -165.8mA   -806.5mA   -43.65mA
-880mV    -42.87mA   -428.4mA   -27.42mA
-820mV    -17.2mA    -166.5mA   -18.19mA
-760mV    -9.579mA   -46.9mA    -10.67mA
-700mV    -5.036mA   -12.93mA   -5.04mA
2.48V     92.64pA    194.9nA    75.8pA
[POWER_clamp]
| voltage   I(typ)   I(min)   I(max)
-2.5V     14.68A     15.52A     14.21A
-1.25V    2.627A     3.53A      2.158A
-1.2V     2.177A     3.077A     1.722A
-1.15V    1.736A     2.631A     1.304A
-1.05V    907.7mA    1.767A     573.8mA
-1V       543.6mA    1.358A     298.7mA
-950mV    250.4mA    972.4mA    111.1mA
-900mV    74.93mA    624.5mA    26.06mA
-850mV    15.02mA    336.8mA    4.862mA
-800mV    3.029mA    139.7mA    1.53mA
-750mV    983.5uA    43.42mA    893.5uA
0V        94.62pA    2.097nA    88.2pA
[Ramp]
| variable   typ   min   max
dV/dt_r   0.5633/2.2854n   0.3137/4.1631n   0.8251/1.2650n
dV/dt_f   0.5669/2.7759n   0.3086/4.1938n   0.8205/1.7246n
R_load = 50.0000
[Rising Waveform]
R_fixture = 50.0000
V_fixture = 0.000
V_fixture_min = 0.000
V_fixture_max = 0.000
| time   V(typ)   V(min)   V(max)
0s        1.087nV    26.48nV    576pV
505.1ps   1.832mV    -76.56uV   -20.25mV
707.1ps   -18.93mV   711uV      215mV
1.01ns    147.4mV    -5.185mV   299mV
2.121ns   345.8mV    88.65mV    1.051V
3.333ns   656.2mV    158.4mV    1.33V
4.546ns   837.2mV    262.6mV    1.368V
6.263ns   920.7mV    391.5mV    1.375V
10ns      938.8mV    522.9mV    1.375V
19.19ns   939.4mV    552.9mV    1.375V
[Rising Waveform]
R_fixture = 50.0000
V_fixture = 2.5000
V_fixture_min = 2.2500
V_fixture_max = 2.7500
| time   V(typ)   V(min)   V(max)
0s        1.55V      1.692V     1.382V
424.2ps   1.551V     1.691V     1.351V
484.8ps   1.544V     1.691V     1.537V
606.1ps   1.522V     1.693V     2.498V
666.7ps   1.64V      1.693V     2.651V
787.9ps   2.215V     1.679V     2.718V
969.7ps   2.474V     1.674V     2.728V
1.273ns   2.489V     2.157V     2.736V
1.576ns   2.49V      2.244V     2.742V
13.74ns   2.5V       2.25V      2.75V
[Falling Waveform]
R_fixture = 50.0000
V_fixture = 0.000
V_fixture_min = 0.000
V_fixture_max = 0.000
| time   V(typ)   V(min)   V(max)
0s        939.4mV    553.1mV    1.375V
404ps     939.4mV    554.1mV    1.393V
505.1ps   954.3mV    553.6mV    1.103V
606.1ps   935.8mV    552.9mV    362.4mV
707.1ps   608.5mV    559.6mV    85.56mV
808.1ps   216.9mV    574.5mV    23.43mV
909.1ps   64.17mV    563.8mV    13.4mV
1.313ns   5.786mV    49.32mV    5.306mV
1.616ns   4.112mV    5.663mV    2.924mV
19.6ns    20.65nV    2.563uV    656.2pV
[Falling Waveform]
R_fixture = 50.0000
V_fixture = 2.5000
V_fixture_min = 2.2500
V_fixture_max = 2.7500
| time   V(typ)   V(min)   V(max)
0s        2.5V       2.25V      2.75V
606.1ps   2.513V     2.25V      2.793V
808.1ps   2.548V     2.249V     2.577V
1.111ns   2.387V     2.281V     2.42V
1.717ns   2.267V     2.191V     2.065V
2.525ns   2.065V     2.14V      1.717V
4.141ns   1.766V     2.006V     1.456V
6.061ns   1.614V     1.864V     1.393V
9.495ns   1.557V     1.744V     1.383V
20ns      1.55V      1.693V     1.382V
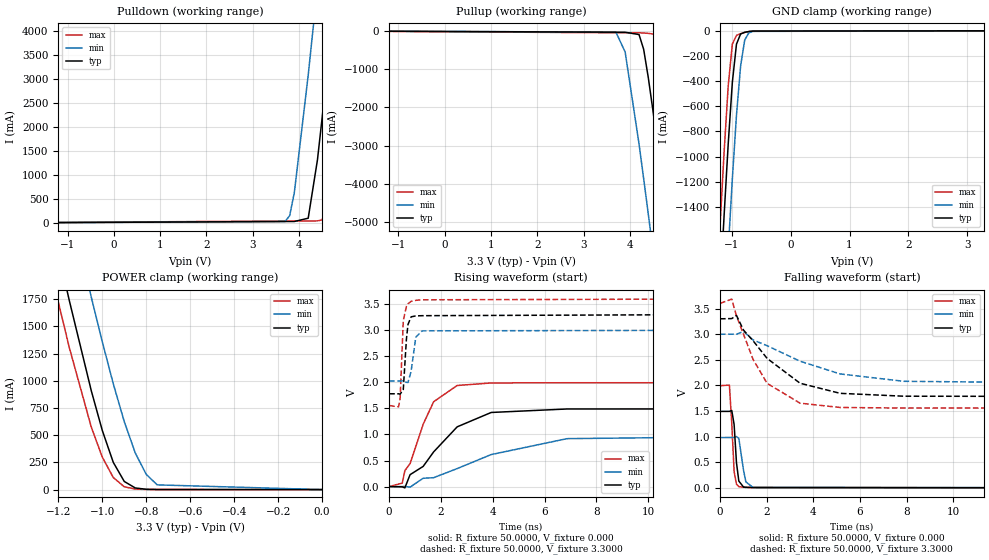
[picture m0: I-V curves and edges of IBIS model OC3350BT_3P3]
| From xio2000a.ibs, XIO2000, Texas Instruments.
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|   Model OC3350BT_3P3
[Model]   OC3350BT_3P3
Model_type   3-state
Enable   Active-Low
Polarity   Non-Inverting
|Vinl =   0.99000V
|Vinh =   2.31000V
Vmeas = 1.65V
Cref = 15pF
Rref = 100e+06
Vref = 0V
|   typ   min   max
C_comp   1.970pF   2.063pF   1.973pF
|   typ   min   max
[Temperature Range]   25   125   -40
|   typ   min   max
[Voltage Range]   3.30V   3.00V   3.60V
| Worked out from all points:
|   slope of the pulldown table from 0 to 0.495 V, typ, clamps not added: 31.4 ohm
|   slope of the pullup table from 0 to 0.495 V, typ, clamps not added: 44.5 ohm
|   GND clamp passes 1 mA (typ) near -0.59 V on its own axis
|   POWER clamp passes 1 mA (typ) near -0.75 V on its own axis
|   rising waveform, R_fixture 50.0000, V_fixture 0.000: 20-80 % time 1.62ns typ, 3.13ns min, 932ps max; typ from 0 V to 1.49 V
|   rising waveform, R_fixture 50.0000, V_fixture 3.3000: 20-80 % time 125ps typ, 153ps min, 103ps max; typ from 1.78 V to 3.3 V
|   falling waveform, R_fixture 50.0000, V_fixture 0.000: 20-80 % time 149ps typ, 196ps min, 138ps max; typ from 1.49 V to 0 V
|   falling waveform, R_fixture 50.0000, V_fixture 3.3000: 20-80 % time 2.06ns typ, 3.32ns min, 1.33ns max; typ from 3.3 V to 1.78 V
| (Vdd votage range)   1.50V   1.35V   1.65V
[Pulldown]
| voltage   I(typ)   I(min)   I(max)
-3.3V     -362uA     -290uA     -391uA
3.7V      31.67mA    31.13mA    42.49mA
3.8V      31.75mA    154.3mA    42.56mA
3.9V      31.94mA    631.8mA    42.64mA
4.2V      100.2mA    3.079A     43.08mA
4.4V      1.316A     4.917A     44.62mA
4.5V      2.18A      5.857A     65.93mA
4.6V      3.088A     6.805A     322mA
4.8V      4.962A     8.72A      1.728A
4.9V      5.916A     9.684A     2.611A
5.2V      8.811A     12.59A     5.427A
6.6V      22.57A     26.34A     19.14A
[Pullup]
| voltage   I(typ)   I(min)   I(max)
-3.3V     276uA      222uA      319uA
3.7V      -35.74mA   -34.2mA    -51mA
3.9V      -36.94mA   -552.8mA   -51.23mA
4.2V      -97.38mA   -2.958A    -52.14mA
4.3V      -483.5mA   -3.866A    -56.28mA
4.4V      -1.222A    -4.791A    -66.54mA
4.5V      -2.079A    -5.729A    -81.95mA
4.6V      -2.984A    -6.677A    -169.7mA
4.8V      -4.856A    -8.59A     -1.567A
5.1V      -7.735A    -11.49A    -4.352A
5.2V      -8.705A    -12.46A    -5.311A
6.6V      -22.46A    -26.21A    -19.05A
[GND_clamp]
| voltage   I(typ)   I(min)   I(max)
-3.3V     -22.46A    -23.25A    -22.02A
-1.2V     -2.075A    -2.956A    -1.561A
-1.13V    -1.466A    -2.337A    -962.1mA
-1.06V    -896.3mA   -1.739A    -435.1mA
-990mV    -408.4mA   -1.175A    -105.4mA
-920mV    -105.8mA   -670.8mA   -36.12mA
-850mV    -25.21mA   -279.7mA   -22.55mA
-780mV    -11.58mA   -73.13mA   -12.99mA
-710mV    -5.673mA   -15.82mA   -5.823mA
-640mV    -2.142mA   -4.365mA   -1.734mA
3.28V     126.5pA    680.7nA    100.8pA
[POWER_clamp]
| voltage   I(typ)   I(min)   I(max)
-3.3V     22.56A     23.38A     22.11A
-1.25V    2.627A     3.53A      2.158A
-1.2V     2.177A     3.077A     1.722A
-1.15V    1.736A     2.631A     1.304A
-1.05V    907.7mA    1.767A     573.8mA
-1V       543.6mA    1.358A     298.7mA
-950mV    250.4mA    972.4mA    111.1mA
-900mV    74.93mA    624.5mA    26.06mA
-850mV    15.02mA    336.8mA    4.862mA
-800mV    3.029mA    139.7mA    1.53mA
-750mV    983.5uA    43.42mA    893.5uA
0V        128.7pA    2.647nA    115.8pA
[Ramp]
| variable   typ   min   max
dV/dt_r   0.8953/1.6045n   0.5841/3.1055n   1.1967/0.9223n
dV/dt_f   0.9101/2.0348n   0.5724/3.2561n   1.2256/1.3186n
R_load = 50.0000
[Rising Waveform]
R_fixture = 50.0000
V_fixture = 0.000
V_fixture_min = 0.000
V_fixture_max = 0.000
| time   V(typ)   V(min)   V(max)
0s        1.527nV    32.71nV    724.5pV
505.1ps   -5.373mV   -160.7uV   65.67mV
606.1ps   -25mV      1.74mV     304.5mV
808.1ps   228.5mV    -11.06mV   442.3mV
1.313ns   387.2mV    159.6mV    1.197V
1.717ns   665.7mV    170.4mV    1.629V
2.626ns   1.147V     345.2mV    1.941V
3.939ns   1.423V     614.4mV    1.99V
6.869ns   1.49V      920.3mV    1.994V
18.38ns   1.492V     981.6mV    1.994V
[Rising Waveform]
R_fixture = 50.0000
V_fixture = 3.3000
V_fixture_min = 3.0000
V_fixture_max = 3.6000
| time   V(typ)   V(min)   V(max)
0s        1.782V     2.028V     1.557V
363.6ps   1.782V     2.027V     1.531V
424.2ps   1.774V     2.027V     1.697V
545.5ps   1.863V     2.029V     3.187V
666.7ps   2.833V     2.002V     3.462V
727.3ps   3.114V     1.999V     3.51V
848.5ps   3.26V      2.217V     3.558V
1.03ns    3.278V     2.872V     3.577V
1.273ns   3.282V     2.99V      3.587V
11.11ns   3.3V       3V         3.6V
[Falling Waveform]
R_fixture = 50.0000
V_fixture = 0.000
V_fixture_min = 0.000
V_fixture_max = 0.000
| time   V(typ)   V(min)   V(max)
0s        1.492V     981.6mV    1.994V
404ps     1.493V     982.5mV    2.006V
505.1ps   1.51V      981.7mV    1.259V
606.1ps   1.236V     985.4mV    316.3mV
707.1ps   489.4mV    1.002V     71.57mV
808.1ps   132.4mV    965.2mV    23.89mV
1.01ns    15.26mV    340.4mV    11.33mV
1.111ns   11.08mV    116.2mV    9.236mV
1.414ns   6.906mV    8.591mV    4.47mV
20ns      2.075nV    321.9nV    815pV
[Falling Waveform]
R_fixture = 50.0000
V_fixture = 3.3000
V_fixture_min = 3.0000
V_fixture_max = 3.6000
| time   V(typ)   V(min)   V(max)
0s        3.3V       3V         3.6V
505.1ps   3.304V     3V         3.684V
707.1ps   3.365V     2.999V     3.356V
1.01ns    3.079V     3.053V     2.996V
1.414ns   2.874V     2.888V     2.513V
2.02ns    2.527V     2.775V     2.04V
3.434ns   2.042V     2.472V     1.653V
5.152ns   1.845V     2.224V     1.569V
7.879ns   1.789V     2.08V      1.558V
20ns      1.782V     2.028V     1.557V
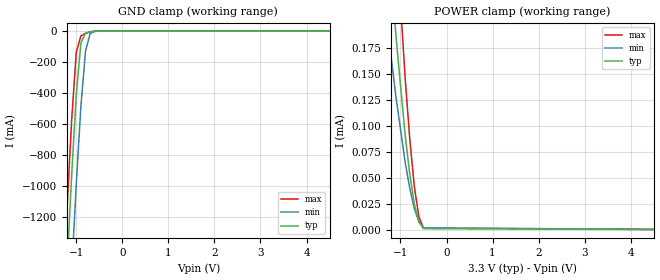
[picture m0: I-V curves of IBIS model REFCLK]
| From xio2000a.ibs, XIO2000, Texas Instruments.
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[Model]   REFCLK
Model_type   Input
Polarity   Non-Inverting
Vinh = 0.7V
Vinl = 0.0V
|   typ   min   max
C_comp   2.0pF   1.5pF   3.0pF
[Model Spec]
|   typ   min   max
Vinh   0.7V   0.30V   1.15V
Vinl   0.0V   -0.30V   0.15V
[Temperature Range]   25   125   -40
[Voltage Range]   3.3V   3.0V   3.6V
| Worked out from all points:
|   GND clamp passes 1 mA (typ) near -0.60 V on its own axis
[GND clamp]
-3.3V     -15.11A    -15.68A    -14.79A
-1.3V     -2.117A    -2.748A    -1.746A
-1.2V     -1.509A    -2.139A    -1.139A
-1.1V     -928.4mA   -1.547A    -571.1mA
-1V       -408.7mA   -985.4mA   -136.1mA
-900mV    -76.3mA    -484.2mA   -30.76mA
-800mV    -14.18mA   -130.2mA   -15.13mA
-700mV    -4.933mA   -16.19mA   -4.943mA
-600mV    -1.015mA   -2.427mA   -690.2uA
-500mV    -99.99uA   -374.7uA   -41.15uA
6.6V      0A         0A         0A
[POWER clamp]
-3.3V     902.4uA    547.2uA    1.298mA
-1.5V     436.9uA    295.6uA    638.1uA
-1.4V     368.6uA    249.4uA    545uA
-1.3V     303.9uA    205.9uA    455.3uA
-1.2V     243.3uA    165.5uA    369.7uA
-1.1V     187.3uA    128.5uA    289.1uA
-900mV    92uA       65.51uA    147uA
-800mV    54.3uA     40.41uA    88.58uA
-700mV    25.33uA    20.7uA     42.11uA
-600mV    7.719uA    7.808uA    12.57uA
-500mV    1.318uA    1.964uA    1.824uA
6.6V      0A         0A         0A
